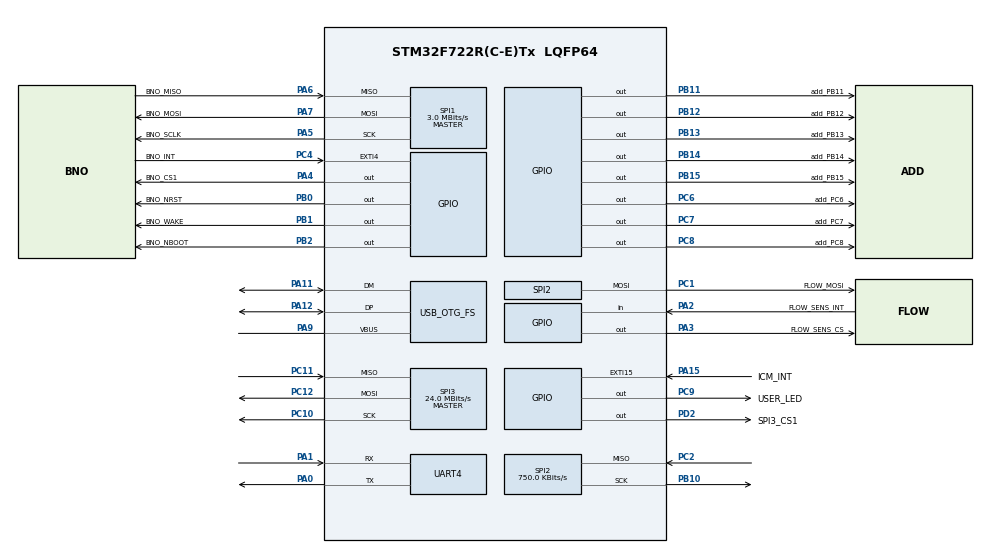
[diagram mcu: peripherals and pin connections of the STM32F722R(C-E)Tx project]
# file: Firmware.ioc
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CORTEX_M7.default_mode_Activation=1
Mcu.Family=STM32F7
Mcu.Name=STM32F722R(C-E)Tx
Mcu.Package=LQFP64
NVIC.EXTI4_IRQn=true\:5\:0\:false\:false\:true\:true\:true\:true
NVIC.PriorityGroup=NVIC_PRIORITYGROUP_4
PA0-WKUP.Mode=Asynchronous
PA0-WKUP.Signal=UART4_TX
PA1.Mode=Asynchronous
PA1.Signal=UART4_RX
PA11.Mode=Device_Only
PA11.Signal=USB_OTG_FS_DM
PA12.Mode=Device_Only
PA12.Signal=USB_OTG_FS_DP
PA13.Mode=Trace_Asynchronous_SW
PA13.Signal=SYS_JTMS-SWDIO
PA14.Mode=Trace_Asynchronous_SW
PA14.Signal=SYS_JTCK-SWCLK
PA15.GPIO_Label=ICM_INT
PA15.Signal=GPXTI15
PA2.GPIO_Label=FLOW_SENS_INT
PA2.GPIO_PuPd=GPIO_PULLUP
PA2.Signal=GPIO_Input
PA3.GPIO_Label=FLOW_SENS_CS
PA3.PinState=GPIO_PIN_SET
PA3.Signal=GPIO_Output
PA4.GPIO_Label=BNO_CS1
PA4.PinState=GPIO_PIN_SET
PA4.Signal=GPIO_Output
PA5.GPIO_Label=BNO_SCLK
PA5.Mode=Full_Duplex_Master
PA5.Signal=SPI1_SCK
PA6.GPIO_Label=BNO_MISO
PA6.Mode=Full_Duplex_Master
PA6.Signal=SPI1_MISO
PA7.GPIO_Label=BNO_MOSI
PA7.Mode=Full_Duplex_Master
PA7.Signal=SPI1_MOSI
PA9.Mode=Activate_VBUS
PA9.Signal=USB_OTG_FS_VBUS
PB0.GPIO_Label=BNO_NRST
PB0.PinState=GPIO_PIN_SET
PB0.Signal=GPIO_Output
PB1.GPIO_Label=BNO_WAKE
PB1.PinState=GPIO_PIN_SET
PB1.Signal=GPIO_Output
PB10.Mode=Full_Duplex_Master
PB10.Signal=SPI2_SCK
PB11.GPIO_Label=add_PB11
PB11.Signal=GPIO_Output
PB12.GPIO_Label=add_PB12
PB12.Signal=GPIO_Output
PB13.GPIO_Label=add_PB13
PB13.Signal=GPIO_Output
PB14.GPIO_Label=add_PB14
PB14.Signal=GPIO_Output
PB15.GPIO_Label=add_PB15
PB15.Signal=GPIO_Output
PB2.GPIO_Label=BNO_NBOOT
PB2.PinState=GPIO_PIN_SET
PB2.Signal=GPIO_Output
PB3.Mode=Trace_Asynchronous_SW
PB3.Signal=SYS_JTDO-SWO
PC1.GPIO_Label=FLOW_MOSI
PC1.Mode=Full_Duplex_Master
PC1.Signal=SPI2_MOSI
PC10.Mode=Full_Duplex_Master
PC10.Signal=SPI3_SCK
PC11.Mode=Full_Duplex_Master
PC11.Signal=SPI3_MISO
PC12.Mode=Full_Duplex_Master
PC12.Signal=SPI3_MOSI
PC14-OSC32_IN.Mode=LSE-External-Clock-Source
PC14-OSC32_IN.Signal=RCC_OSC32_IN
PC15-OSC32_OUT.Mode=LSE-External-Clock-Source
PC15-OSC32_OUT.Signal=RCC_OSC32_OUT
PC2.Mode=Full_Duplex_Master
PC2.Signal=SPI2_MISO
PC4.GPIO_Label=BNO_INT
PC4.GPIO_ModeDefaultEXTI=GPIO_MODE_IT_FALLING
PC4.GPIO_PuPd=GPIO_PULLUP
PC4.Signal=GPXTI4
PC6.GPIO_Label=add_PC6
PC6.Signal=GPIO_Output
PC7.GPIO_Label=add_PC7
PC7.Signal=GPIO_Output
PC8.GPIO_Label=add_PC8
PC8.Signal=GPIO_Output
PC9.GPIO_Label=USER_LED
PC9.Signal=GPIO_Output
PD2.GPIO_Label=SPI3_CS1
PD2.PinState=GPIO_PIN_SET
PD2.Signal=GPIO_Output
PH0-OSC_IN.Mode=HSE-External-Oscillator
PH0-OSC_IN.Signal=RCC_OSC_IN
PH1-OSC_OUT.Mode=HSE-External-Oscillator
PH1-OSC_OUT.Signal=RCC_OSC_OUT
ProjectManager.HeapSize=0x200
ProjectManager.StackSize=0x400
ProjectManager.TargetToolchain=CMake
RCC.AHBFreq_Value=192000000
RCC.APB1CLKDivider=RCC_HCLK_DIV4
RCC.APB1Freq_Value=48000000
RCC.APB1TimFreq_Value=96000000
RCC.APB2CLKDivider=RCC_HCLK_DIV2
RCC.APB2Freq_Value=96000000
RCC.APB2TimFreq_Value=192000000
RCC.CortexFreq_Value=192000000
RCC.HCLKFreq_Value=192000000
RCC.HSE_VALUE=12000000
RCC.HSI_VALUE=16000000
RCC.LSE_VALUE=32768
RCC.PLLM=6
RCC.PLLQ=8
RCC.SYSCLKFreq_VALUE=192000000
RCC.SYSCLKSource=RCC_SYSCLKSOURCE_PLLCLK
RCC.USBFreq_Value=48000000
RCC.VCOOutputFreq_Value=384000000
SPI1.BaudRatePrescaler=SPI_BAUDRATEPRESCALER_32
SPI1.CLKPhase=SPI_PHASE_2EDGE
SPI1.CLKPolarity=SPI_POLARITY_HIGH
SPI1.CalculateBaudRate=3.0 MBits/s
SPI1.DataSize=SPI_DATASIZE_8BIT
SPI1.Direction=SPI_DIRECTION_2LINES
SPI1.Mode=SPI_MODE_MASTER
SPI1.VirtualType=VM_MASTER
SPI2.BaudRatePrescaler=SPI_BAUDRATEPRESCALER_64
SPI2.CLKPhase=SPI_PHASE_2EDGE
SPI2.CLKPolarity=SPI_POLARITY_HIGH
SPI2.CalculateBaudRate=750.0 KBits/s
SPI2.DataSize=SPI_DATASIZE_8BIT
SPI2.Direction=SPI_DIRECTION_2LINES
SPI2.Mode=SPI_MODE_MASTER
SPI2.VirtualType=VM_MASTER
SPI3.CalculateBaudRate=24.0 MBits/s
SPI3.Direction=SPI_DIRECTION_2LINES
SPI3.Mode=SPI_MODE_MASTER
SPI3.VirtualType=VM_MASTER
USB_OTG_FS.VirtualMode=Device_Only
board=custom

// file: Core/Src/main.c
/* USER CODE BEGIN Header */
/**
  ******************************************************************************
  * @file           : main.c
  * @brief          : Main program body
  ******************************************************************************
  * @attention
  *
  * Copyright (c) 2026 STMicroelectronics.
  * All rights reserved.
  *
  * This software is licensed under terms that can be found in the LICENSE file
  * in the root directory of this software component.
  * If no LICENSE file comes with this software, it is provided AS-IS.
  *
  ******************************************************************************
  */
/* USER CODE END Header */
#include "main.h"
#include "spi.h"
#include "usart.h"
#include "usb_otg.h"
#include "gpio.h"

/* USER CODE BEGIN Includes */
#include "app.h"
/* USER CODE END Includes */

void SystemClock_Config(void);
static void MPU_Config(void);

int main(void)
{

  /* MPU Configuration--------------------------------------------------------*/
  MPU_Config();

  /* MCU Configuration--------------------------------------------------------*/

  /* Reset of all peripherals, Initializes the Flash interface and the Systick. */
  HAL_Init();

  /* Configure the system clock */
  SystemClock_Config();

  /* Initialize all configured peripherals */
  MX_GPIO_Init();
  MX_SPI1_Init();
  MX_USB_OTG_FS_PCD_Init();
  MX_SPI3_Init();
  MX_SPI2_Init();
  MX_UART4_Init();
  /* USER CODE BEGIN 2 */
  //HAL_GPIO_TogglePin(USER_LED_GPIO_Port, USER_LED_Pin);
  app_main();
  /* USER CODE END 2 */

  /* Infinite loop */
  while (1)
  {

  }
}

void SystemClock_Config(void)
{
  RCC_OscInitTypeDef RCC_OscInitStruct = {0};
  RCC_ClkInitTypeDef RCC_ClkInitStruct = {0};

  /** Configure the main internal regulator output voltage
  */
  __HAL_RCC_PWR_CLK_ENABLE();
  __HAL_PWR_VOLTAGESCALING_CONFIG(PWR_REGULATOR_VOLTAGE_SCALE1);

  /** Initializes the RCC Oscillators according to the specified parameters
  * in the RCC_OscInitTypeDef structure.
  */
  RCC_OscInitStruct.OscillatorType = RCC_OSCILLATORTYPE_HSE;
  RCC_OscInitStruct.HSEState = RCC_HSE_ON;
  RCC_OscInitStruct.PLL.PLLState = RCC_PLL_ON;
  RCC_OscInitStruct.PLL.PLLSource = RCC_PLLSOURCE_HSE;
  RCC_OscInitStruct.PLL.PLLM = 6;
  RCC_OscInitStruct.PLL.PLLN = 192;
  /* Power-Saving: SYSCLK 192 -> 96 MHz (PLLP /2 -> /4).  Halbiert die
   * Core-Dynamic-Power.  USB bleibt 48 MHz (PLLQ=8 unabhängig von PLLP).
   * delay_us() in paa5100.c ist auf 96 MHz kalibriert (us*32).  HINWEIS:
   * CubeMX-Code ohne USER-CODE-Marker — bei .ioc-Regen überschrieben. */
  RCC_OscInitStruct.PLL.PLLP = RCC_PLLP_DIV4;
  RCC_OscInitStruct.PLL.PLLQ = 8;
  if (HAL_RCC_OscConfig(&RCC_OscInitStruct) != HAL_OK)
  {
    Error_Handler();
  }

  /** Activate the Over-Drive mode
  */
  if (HAL_PWREx_EnableOverDrive() != HAL_OK)
  {
    Error_Handler();
  }

  /** Initializes the CPU, AHB and APB buses clocks
  */
  RCC_ClkInitStruct.ClockType = RCC_CLOCKTYPE_HCLK|RCC_CLOCKTYPE_SYSCLK
                              |RCC_CLOCKTYPE_PCLK1|RCC_CLOCKTYPE_PCLK2;
  RCC_ClkInitStruct.SYSCLKSource = RCC_SYSCLKSOURCE_PLLCLK;
  RCC_ClkInitStruct.AHBCLKDivider = RCC_SYSCLK_DIV1;
  RCC_ClkInitStruct.APB1CLKDivider = RCC_HCLK_DIV4;
  RCC_ClkInitStruct.APB2CLKDivider = RCC_HCLK_DIV2;

  if (HAL_RCC_ClockConfig(&RCC_ClkInitStruct, FLASH_LATENCY_6) != HAL_OK)
  {
    Error_Handler();
  }
}

 /* MPU Configuration */

void MPU_Config(void)
{
  MPU_Region_InitTypeDef MPU_InitStruct = {0};

  /* Disables the MPU */
  HAL_MPU_Disable();

  /** Initializes and configures the Region and the memory to be protected
  */
  MPU_InitStruct.Enable = MPU_REGION_ENABLE;
  MPU_InitStruct.Number = MPU_REGION_NUMBER0;
  MPU_InitStruct.BaseAddress = 0x0;
  MPU_InitStruct.Size = MPU_REGION_SIZE_4GB;
  MPU_InitStruct.SubRegionDisable = 0x87;
  MPU_InitStruct.TypeExtField = MPU_TEX_LEVEL0;
  MPU_InitStruct.AccessPermission = MPU_REGION_NO_ACCESS;
  MPU_InitStruct.DisableExec = MPU_INSTRUCTION_ACCESS_DISABLE;
  MPU_InitStruct.IsShareable = MPU_ACCESS_SHAREABLE;
  MPU_InitStruct.IsCacheable = MPU_ACCESS_NOT_CACHEABLE;
  MPU_InitStruct.IsBufferable = MPU_ACCESS_NOT_BUFFERABLE;

  HAL_MPU_ConfigRegion(&MPU_InitStruct);
  /* Enables the MPU */
  HAL_MPU_Enable(MPU_PRIVILEGED_DEFAULT);

}

void Error_Handler(void)
{
  __disable_irq();
  while (1)
  {
  }
}
